# Generated by FakeRAM 2.0
VERSION 5.7 ;
BUSBITCHARS "[]" ;
PROPERTYDEFINITIONS
  MACRO width INTEGER ;
  MACRO depth INTEGER ;
  MACRO banks INTEGER ;
END PROPERTYDEFINITIONS
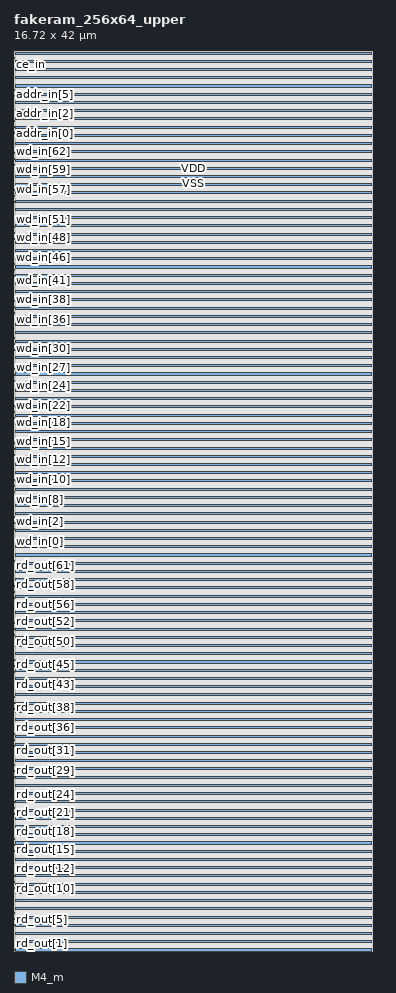
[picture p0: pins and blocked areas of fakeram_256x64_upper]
MACRO fakeram_256x64_upper
  PROPERTY width 64 ;
  PROPERTY depth 256 ;
  PROPERTY banks 2 ;
  FOREIGN fakeram_256x64_upper 0 0 ;
  SYMMETRY X Y R90 ;
  SIZE 16.720 BY 42.000 ;
  CLASS BLOCK ;
  PIN rd_out[0]
    DIRECTION OUTPUT ;
    USE SIGNAL ;
    SHAPE ABUTMENT ;
    PORT
      LAYER M4_m ;
      RECT 0.000 0.039 0.024 0.063 ;
    END
  END rd_out[0]
  PIN rd_out[1]
    DIRECTION OUTPUT ;
    USE SIGNAL ;
    SHAPE ABUTMENT ;
    PORT
      LAYER M4_m ;
      RECT 0.000 0.327 0.024 0.351 ;
    END
  END rd_out[1]
  PIN rd_out[2]
    DIRECTION OUTPUT ;
    USE SIGNAL ;
    SHAPE ABUTMENT ;
    PORT
      LAYER M4_m ;
      RECT 0.000 0.615 0.024 0.639 ;
    END
  END rd_out[2]
  PIN rd_out[3]
    DIRECTION OUTPUT ;
    USE SIGNAL ;
    SHAPE ABUTMENT ;
    PORT
      LAYER M4_m ;
      RECT 0.000 0.903 0.024 0.927 ;
    END
  END rd_out[3]
  PIN rd_out[4]
    DIRECTION OUTPUT ;
    USE SIGNAL ;
    SHAPE ABUTMENT ;
    PORT
      LAYER M4_m ;
      RECT 0.000 1.191 0.024 1.215 ;
    END
  END rd_out[4]
  PIN rd_out[5]
    DIRECTION OUTPUT ;
    USE SIGNAL ;
    SHAPE ABUTMENT ;
    PORT
      LAYER M4_m ;
      RECT 0.000 1.479 0.024 1.503 ;
    END
  END rd_out[5]
  PIN rd_out[6]
    DIRECTION OUTPUT ;
    USE SIGNAL ;
    SHAPE ABUTMENT ;
    PORT
      LAYER M4_m ;
      RECT 0.000 1.767 0.024 1.791 ;
    END
  END rd_out[6]
  PIN rd_out[7]
    DIRECTION OUTPUT ;
    USE SIGNAL ;
    SHAPE ABUTMENT ;
    PORT
      LAYER M4_m ;
      RECT 0.000 2.055 0.024 2.079 ;
    END
  END rd_out[7]
  PIN rd_out[8]
    DIRECTION OUTPUT ;
    USE SIGNAL ;
    SHAPE ABUTMENT ;
    PORT
      LAYER M4_m ;
      RECT 0.000 2.343 0.024 2.367 ;
    END
  END rd_out[8]
  PIN rd_out[9]
    DIRECTION OUTPUT ;
    USE SIGNAL ;
    SHAPE ABUTMENT ;
    PORT
      LAYER M4_m ;
      RECT 0.000 2.631 0.024 2.655 ;
    END
  END rd_out[9]
  PIN rd_out[10]
    DIRECTION OUTPUT ;
    USE SIGNAL ;
    SHAPE ABUTMENT ;
    PORT
      LAYER M4_m ;
      RECT 0.000 2.919 0.024 2.943 ;
    END
  END rd_out[10]
  PIN rd_out[11]
    DIRECTION OUTPUT ;
    USE SIGNAL ;
    SHAPE ABUTMENT ;
    PORT
      LAYER M4_m ;
      RECT 0.000 3.207 0.024 3.231 ;
    END
  END rd_out[11]
  PIN rd_out[12]
    DIRECTION OUTPUT ;
    USE SIGNAL ;
    SHAPE ABUTMENT ;
    PORT
      LAYER M4_m ;
      RECT 0.000 3.495 0.024 3.519 ;
    END
  END rd_out[12]
  PIN rd_out[13]
    DIRECTION OUTPUT ;
    USE SIGNAL ;
    SHAPE ABUTMENT ;
    PORT
      LAYER M4_m ;
      RECT 0.000 3.783 0.024 3.807 ;
    END
  END rd_out[13]
  PIN rd_out[14]
    DIRECTION OUTPUT ;
    USE SIGNAL ;
    SHAPE ABUTMENT ;
    PORT
      LAYER M4_m ;
      RECT 0.000 4.071 0.024 4.095 ;
    END
  END rd_out[14]
  PIN rd_out[15]
    DIRECTION OUTPUT ;
    USE SIGNAL ;
    SHAPE ABUTMENT ;
    PORT
      LAYER M4_m ;
      RECT 0.000 4.359 0.024 4.383 ;
    END
  END rd_out[15]
  PIN rd_out[16]
    DIRECTION OUTPUT ;
    USE SIGNAL ;
    SHAPE ABUTMENT ;
    PORT
      LAYER M4_m ;
      RECT 0.000 4.647 0.024 4.671 ;
    END
  END rd_out[16]
  PIN rd_out[17]
    DIRECTION OUTPUT ;
    USE SIGNAL ;
    SHAPE ABUTMENT ;
    PORT
      LAYER M4_m ;
      RECT 0.000 4.935 0.024 4.959 ;
    END
  END rd_out[17]
  PIN rd_out[18]
    DIRECTION OUTPUT ;
    USE SIGNAL ;
    SHAPE ABUTMENT ;
    PORT
      LAYER M4_m ;
      RECT 0.000 5.223 0.024 5.247 ;
    END
  END rd_out[18]
  PIN rd_out[19]
    DIRECTION OUTPUT ;
    USE SIGNAL ;
    SHAPE ABUTMENT ;
    PORT
      LAYER M4_m ;
      RECT 0.000 5.511 0.024 5.535 ;
    END
  END rd_out[19]
  PIN rd_out[20]
    DIRECTION OUTPUT ;
    USE SIGNAL ;
    SHAPE ABUTMENT ;
    PORT
      LAYER M4_m ;
      RECT 0.000 5.799 0.024 5.823 ;
    END
  END rd_out[20]
  PIN rd_out[21]
    DIRECTION OUTPUT ;
    USE SIGNAL ;
    SHAPE ABUTMENT ;
    PORT
      LAYER M4_m ;
      RECT 0.000 6.087 0.024 6.111 ;
    END
  END rd_out[21]
  PIN rd_out[22]
    DIRECTION OUTPUT ;
    USE SIGNAL ;
    SHAPE ABUTMENT ;
    PORT
      LAYER M4_m ;
      RECT 0.000 6.375 0.024 6.399 ;
    END
  END rd_out[22]
  PIN rd_out[23]
    DIRECTION OUTPUT ;
    USE SIGNAL ;
    SHAPE ABUTMENT ;
    PORT
      LAYER M4_m ;
      RECT 0.000 6.663 0.024 6.687 ;
    END
  END rd_out[23]
  PIN rd_out[24]
    DIRECTION OUTPUT ;
    USE SIGNAL ;
    SHAPE ABUTMENT ;
    PORT
      LAYER M4_m ;
      RECT 0.000 6.951 0.024 6.975 ;
    END
  END rd_out[24]
  PIN rd_out[25]
    DIRECTION OUTPUT ;
    USE SIGNAL ;
    SHAPE ABUTMENT ;
    PORT
      LAYER M4_m ;
      RECT 0.000 7.239 0.024 7.263 ;
    END
  END rd_out[25]
  PIN rd_out[26]
    DIRECTION OUTPUT ;
    USE SIGNAL ;
    SHAPE ABUTMENT ;
    PORT
      LAYER M4_m ;
      RECT 0.000 7.527 0.024 7.551 ;
    END
  END rd_out[26]
  PIN rd_out[27]
    DIRECTION OUTPUT ;
    USE SIGNAL ;
    SHAPE ABUTMENT ;
    PORT
      LAYER M4_m ;
      RECT 0.000 7.815 0.024 7.839 ;
    END
  END rd_out[27]
  PIN rd_out[28]
    DIRECTION OUTPUT ;
    USE SIGNAL ;
    SHAPE ABUTMENT ;
    PORT
      LAYER M4_m ;
      RECT 0.000 8.103 0.024 8.127 ;
    END
  END rd_out[28]
  PIN rd_out[29]
    DIRECTION OUTPUT ;
    USE SIGNAL ;
    SHAPE ABUTMENT ;
    PORT
      LAYER M4_m ;
      RECT 0.000 8.391 0.024 8.415 ;
    END
  END rd_out[29]
  PIN rd_out[30]
    DIRECTION OUTPUT ;
    USE SIGNAL ;
    SHAPE ABUTMENT ;
    PORT
      LAYER M4_m ;
      RECT 0.000 8.679 0.024 8.703 ;
    END
  END rd_out[30]
  PIN rd_out[31]
    DIRECTION OUTPUT ;
    USE SIGNAL ;
    SHAPE ABUTMENT ;
    PORT
      LAYER M4_m ;
      RECT 0.000 8.967 0.024 8.991 ;
    END
  END rd_out[31]
  PIN rd_out[32]
    DIRECTION OUTPUT ;
    USE SIGNAL ;
    SHAPE ABUTMENT ;
    PORT
      LAYER M4_m ;
      RECT 0.000 9.255 0.024 9.279 ;
    END
  END rd_out[32]
  PIN rd_out[33]
    DIRECTION OUTPUT ;
    USE SIGNAL ;
    SHAPE ABUTMENT ;
    PORT
      LAYER M4_m ;
      RECT 0.000 9.543 0.024 9.567 ;
    END
  END rd_out[33]
  PIN rd_out[34]
    DIRECTION OUTPUT ;
    USE SIGNAL ;
    SHAPE ABUTMENT ;
    PORT
      LAYER M4_m ;
      RECT 0.000 9.831 0.024 9.855 ;
    END
  END rd_out[34]
  PIN rd_out[35]
    DIRECTION OUTPUT ;
    USE SIGNAL ;
    SHAPE ABUTMENT ;
    PORT
      LAYER M4_m ;
      RECT 0.000 10.119 0.024 10.143 ;
    END
  END rd_out[35]
  PIN rd_out[36]
    DIRECTION OUTPUT ;
    USE SIGNAL ;
    SHAPE ABUTMENT ;
    PORT
      LAYER M4_m ;
      RECT 0.000 10.407 0.024 10.431 ;
    END
  END rd_out[36]
  PIN rd_out[37]
    DIRECTION OUTPUT ;
    USE SIGNAL ;
    SHAPE ABUTMENT ;
    PORT
      LAYER M4_m ;
      RECT 0.000 10.695 0.024 10.719 ;
    END
  END rd_out[37]
  PIN rd_out[38]
    DIRECTION OUTPUT ;
    USE SIGNAL ;
    SHAPE ABUTMENT ;
    PORT
      LAYER M4_m ;
      RECT 0.000 10.983 0.024 11.007 ;
    END
  END rd_out[38]
  PIN rd_out[39]
    DIRECTION OUTPUT ;
    USE SIGNAL ;
    SHAPE ABUTMENT ;
    PORT
      LAYER M4_m ;
      RECT 0.000 11.271 0.024 11.295 ;
    END
  END rd_out[39]
  PIN rd_out[40]
    DIRECTION OUTPUT ;
    USE SIGNAL ;
    SHAPE ABUTMENT ;
    PORT
      LAYER M4_m ;
      RECT 0.000 11.559 0.024 11.583 ;
    END
  END rd_out[40]
  PIN rd_out[41]
    DIRECTION OUTPUT ;
    USE SIGNAL ;
    SHAPE ABUTMENT ;
    PORT
      LAYER M4_m ;
      RECT 0.000 11.847 0.024 11.871 ;
    END
  END rd_out[41]
  PIN rd_out[42]
    DIRECTION OUTPUT ;
    USE SIGNAL ;
    SHAPE ABUTMENT ;
    PORT
      LAYER M4_m ;
      RECT 0.000 12.135 0.024 12.159 ;
    END
  END rd_out[42]
  PIN rd_out[43]
    DIRECTION OUTPUT ;
    USE SIGNAL ;
    SHAPE ABUTMENT ;
    PORT
      LAYER M4_m ;
      RECT 0.000 12.423 0.024 12.447 ;
    END
  END rd_out[43]
  PIN rd_out[44]
    DIRECTION OUTPUT ;
    USE SIGNAL ;
    SHAPE ABUTMENT ;
    PORT
      LAYER M4_m ;
      RECT 0.000 12.711 0.024 12.735 ;
    END
  END rd_out[44]
  PIN rd_out[45]
    DIRECTION OUTPUT ;
    USE SIGNAL ;
    SHAPE ABUTMENT ;
    PORT
      LAYER M4_m ;
      RECT 0.000 12.999 0.024 13.023 ;
    END
  END rd_out[45]
  PIN rd_out[46]
    DIRECTION OUTPUT ;
    USE SIGNAL ;
    SHAPE ABUTMENT ;
    PORT
      LAYER M4_m ;
      RECT 0.000 13.287 0.024 13.311 ;
    END
  END rd_out[46]
  PIN rd_out[47]
    DIRECTION OUTPUT ;
    USE SIGNAL ;
    SHAPE ABUTMENT ;
    PORT
      LAYER M4_m ;
      RECT 0.000 13.575 0.024 13.599 ;
    END
  END rd_out[47]
  PIN rd_out[48]
    DIRECTION OUTPUT ;
    USE SIGNAL ;
    SHAPE ABUTMENT ;
    PORT
      LAYER M4_m ;
      RECT 0.000 13.863 0.024 13.887 ;
    END
  END rd_out[48]
  PIN rd_out[49]
    DIRECTION OUTPUT ;
    USE SIGNAL ;
    SHAPE ABUTMENT ;
    PORT
      LAYER M4_m ;
      RECT 0.000 14.151 0.024 14.175 ;
    END
  END rd_out[49]
  PIN rd_out[50]
    DIRECTION OUTPUT ;
    USE SIGNAL ;
    SHAPE ABUTMENT ;
    PORT
      LAYER M4_m ;
      RECT 0.000 14.439 0.024 14.463 ;
    END
  END rd_out[50]
  PIN rd_out[51]
    DIRECTION OUTPUT ;
    USE SIGNAL ;
    SHAPE ABUTMENT ;
    PORT
      LAYER M4_m ;
      RECT 0.000 14.727 0.024 14.751 ;
    END
  END rd_out[51]
  PIN rd_out[52]
    DIRECTION OUTPUT ;
    USE SIGNAL ;
    SHAPE ABUTMENT ;
    PORT
      LAYER M4_m ;
      RECT 0.000 15.015 0.024 15.039 ;
    END
  END rd_out[52]
  PIN rd_out[53]
    DIRECTION OUTPUT ;
    USE SIGNAL ;
    SHAPE ABUTMENT ;
    PORT
      LAYER M4_m ;
      RECT 0.000 15.303 0.024 15.327 ;
    END
  END rd_out[53]
  PIN rd_out[54]
    DIRECTION OUTPUT ;
    USE SIGNAL ;
    SHAPE ABUTMENT ;
    PORT
      LAYER M4_m ;
      RECT 0.000 15.591 0.024 15.615 ;
    END
  END rd_out[54]
  PIN rd_out[55]
    DIRECTION OUTPUT ;
    USE SIGNAL ;
    SHAPE ABUTMENT ;
    PORT
      LAYER M4_m ;
      RECT 0.000 15.879 0.024 15.903 ;
    END
  END rd_out[55]
  PIN rd_out[56]
    DIRECTION OUTPUT ;
    USE SIGNAL ;
    SHAPE ABUTMENT ;
    PORT
      LAYER M4_m ;
      RECT 0.000 16.167 0.024 16.191 ;
    END
  END rd_out[56]
  PIN rd_out[57]
    DIRECTION OUTPUT ;
    USE SIGNAL ;
    SHAPE ABUTMENT ;
    PORT
      LAYER M4_m ;
      RECT 0.000 16.455 0.024 16.479 ;
    END
  END rd_out[57]
  PIN rd_out[58]
    DIRECTION OUTPUT ;
    USE SIGNAL ;
    SHAPE ABUTMENT ;
    PORT
      LAYER M4_m ;
      RECT 0.000 16.743 0.024 16.767 ;
    END
  END rd_out[58]
  PIN rd_out[59]
    DIRECTION OUTPUT ;
    USE SIGNAL ;
    SHAPE ABUTMENT ;
    PORT
      LAYER M4_m ;
      RECT 0.000 17.031 0.024 17.055 ;
    END
  END rd_out[59]
  PIN rd_out[60]
    DIRECTION OUTPUT ;
    USE SIGNAL ;
    SHAPE ABUTMENT ;
    PORT
      LAYER M4_m ;
      RECT 0.000 17.319 0.024 17.343 ;
    END
  END rd_out[60]
  PIN rd_out[61]
    DIRECTION OUTPUT ;
    USE SIGNAL ;
    SHAPE ABUTMENT ;
    PORT
      LAYER M4_m ;
      RECT 0.000 17.607 0.024 17.631 ;
    END
  END rd_out[61]
  PIN rd_out[62]
    DIRECTION OUTPUT ;
    USE SIGNAL ;
    SHAPE ABUTMENT ;
    PORT
      LAYER M4_m ;
      RECT 0.000 17.895 0.024 17.919 ;
    END
  END rd_out[62]
  PIN rd_out[63]
    DIRECTION OUTPUT ;
    USE SIGNAL ;
    SHAPE ABUTMENT ;
    PORT
      LAYER M4_m ;
      RECT 0.000 18.183 0.024 18.207 ;
    END
  END rd_out[63]
  PIN wd_in[0]
    DIRECTION INPUT ;
    USE SIGNAL ;
    SHAPE ABUTMENT ;
    PORT
      LAYER M4_m ;
      RECT 0.000 19.095 0.024 19.119 ;
    END
  END wd_in[0]
  PIN wd_in[1]
    DIRECTION INPUT ;
    USE SIGNAL ;
    SHAPE ABUTMENT ;
    PORT
      LAYER M4_m ;
      RECT 0.000 19.383 0.024 19.407 ;
    END
  END wd_in[1]
  PIN wd_in[2]
    DIRECTION INPUT ;
    USE SIGNAL ;
    SHAPE ABUTMENT ;
    PORT
      LAYER M4_m ;
      RECT 0.000 19.671 0.024 19.695 ;
    END
  END wd_in[2]
  PIN wd_in[3]
    DIRECTION INPUT ;
    USE SIGNAL ;
    SHAPE ABUTMENT ;
    PORT
      LAYER M4_m ;
      RECT 0.000 19.959 0.024 19.983 ;
    END
  END wd_in[3]
  PIN wd_in[4]
    DIRECTION INPUT ;
    USE SIGNAL ;
    SHAPE ABUTMENT ;
    PORT
      LAYER M4_m ;
      RECT 0.000 20.247 0.024 20.271 ;
    END
  END wd_in[4]
  PIN wd_in[5]
    DIRECTION INPUT ;
    USE SIGNAL ;
    SHAPE ABUTMENT ;
    PORT
      LAYER M4_m ;
      RECT 0.000 20.535 0.024 20.559 ;
    END
  END wd_in[5]
  PIN wd_in[6]
    DIRECTION INPUT ;
    USE SIGNAL ;
    SHAPE ABUTMENT ;
    PORT
      LAYER M4_m ;
      RECT 0.000 20.823 0.024 20.847 ;
    END
  END wd_in[6]
  PIN wd_in[7]
    DIRECTION INPUT ;
    USE SIGNAL ;
    SHAPE ABUTMENT ;
    PORT
      LAYER M4_m ;
      RECT 0.000 21.111 0.024 21.135 ;
    END
  END wd_in[7]
  PIN wd_in[8]
    DIRECTION INPUT ;
    USE SIGNAL ;
    SHAPE ABUTMENT ;
    PORT
      LAYER M4_m ;
      RECT 0.000 21.399 0.024 21.423 ;
    END
  END wd_in[8]
  PIN wd_in[9]
    DIRECTION INPUT ;
    USE SIGNAL ;
    SHAPE ABUTMENT ;
    PORT
      LAYER M4_m ;
      RECT 0.000 21.687 0.024 21.711 ;
    END
  END wd_in[9]
  PIN wd_in[10]
    DIRECTION INPUT ;
    USE SIGNAL ;
    SHAPE ABUTMENT ;
    PORT
      LAYER M4_m ;
      RECT 0.000 21.975 0.024 21.999 ;
    END
  END wd_in[10]
  PIN wd_in[11]
    DIRECTION INPUT ;
    USE SIGNAL ;
    SHAPE ABUTMENT ;
    PORT
      LAYER M4_m ;
      RECT 0.000 22.263 0.024 22.287 ;
    END
  END wd_in[11]
  PIN wd_in[12]
    DIRECTION INPUT ;
    USE SIGNAL ;
    SHAPE ABUTMENT ;
    PORT
      LAYER M4_m ;
      RECT 0.000 22.551 0.024 22.575 ;
    END
  END wd_in[12]
  PIN wd_in[13]
    DIRECTION INPUT ;
    USE SIGNAL ;
    SHAPE ABUTMENT ;
    PORT
      LAYER M4_m ;
      RECT 0.000 22.839 0.024 22.863 ;
    END
  END wd_in[13]
  PIN wd_in[14]
    DIRECTION INPUT ;
    USE SIGNAL ;
    SHAPE ABUTMENT ;
    PORT
      LAYER M4_m ;
      RECT 0.000 23.127 0.024 23.151 ;
    END
  END wd_in[14]
  PIN wd_in[15]
    DIRECTION INPUT ;
    USE SIGNAL ;
    SHAPE ABUTMENT ;
    PORT
      LAYER M4_m ;
      RECT 0.000 23.415 0.024 23.439 ;
    END
  END wd_in[15]
  PIN wd_in[16]
    DIRECTION INPUT ;
    USE SIGNAL ;
    SHAPE ABUTMENT ;
    PORT
      LAYER M4_m ;
      RECT 0.000 23.703 0.024 23.727 ;
    END
  END wd_in[16]
  PIN wd_in[17]
    DIRECTION INPUT ;
    USE SIGNAL ;
    SHAPE ABUTMENT ;
    PORT
      LAYER M4_m ;
      RECT 0.000 23.991 0.024 24.015 ;
    END
  END wd_in[17]
  PIN wd_in[18]
    DIRECTION INPUT ;
    USE SIGNAL ;
    SHAPE ABUTMENT ;
    PORT
      LAYER M4_m ;
      RECT 0.000 24.279 0.024 24.303 ;
    END
  END wd_in[18]
  PIN wd_in[19]
    DIRECTION INPUT ;
    USE SIGNAL ;
    SHAPE ABUTMENT ;
    PORT
      LAYER M4_m ;
      RECT 0.000 24.567 0.024 24.591 ;
    END
  END wd_in[19]
  PIN wd_in[20]
    DIRECTION INPUT ;
    USE SIGNAL ;
    SHAPE ABUTMENT ;
    PORT
      LAYER M4_m ;
      RECT 0.000 24.855 0.024 24.879 ;
    END
  END wd_in[20]
  PIN wd_in[21]
    DIRECTION INPUT ;
    USE SIGNAL ;
    SHAPE ABUTMENT ;
    PORT
      LAYER M4_m ;
      RECT 0.000 25.143 0.024 25.167 ;
    END
  END wd_in[21]
  PIN wd_in[22]
    DIRECTION INPUT ;
    USE SIGNAL ;
    SHAPE ABUTMENT ;
    PORT
      LAYER M4_m ;
      RECT 0.000 25.431 0.024 25.455 ;
    END
  END wd_in[22]
  PIN wd_in[23]
    DIRECTION INPUT ;
    USE SIGNAL ;
    SHAPE ABUTMENT ;
    PORT
      LAYER M4_m ;
      RECT 0.000 25.719 0.024 25.743 ;
    END
  END wd_in[23]
  PIN wd_in[24]
    DIRECTION INPUT ;
    USE SIGNAL ;
    SHAPE ABUTMENT ;
    PORT
      LAYER M4_m ;
      RECT 0.000 26.007 0.024 26.031 ;
    END
  END wd_in[24]
  PIN wd_in[25]
    DIRECTION INPUT ;
    USE SIGNAL ;
    SHAPE ABUTMENT ;
    PORT
      LAYER M4_m ;
      RECT 0.000 26.295 0.024 26.319 ;
    END
  END wd_in[25]
  PIN wd_in[26]
    DIRECTION INPUT ;
    USE SIGNAL ;
    SHAPE ABUTMENT ;
    PORT
      LAYER M4_m ;
      RECT 0.000 26.583 0.024 26.607 ;
    END
  END wd_in[26]
  PIN wd_in[27]
    DIRECTION INPUT ;
    USE SIGNAL ;
    SHAPE ABUTMENT ;
    PORT
      LAYER M4_m ;
      RECT 0.000 26.871 0.024 26.895 ;
    END
  END wd_in[27]
  PIN wd_in[28]
    DIRECTION INPUT ;
    USE SIGNAL ;
    SHAPE ABUTMENT ;
    PORT
      LAYER M4_m ;
      RECT 0.000 27.159 0.024 27.183 ;
    END
  END wd_in[28]
  PIN wd_in[29]
    DIRECTION INPUT ;
    USE SIGNAL ;
    SHAPE ABUTMENT ;
    PORT
      LAYER M4_m ;
      RECT 0.000 27.447 0.024 27.471 ;
    END
  END wd_in[29]
  PIN wd_in[30]
    DIRECTION INPUT ;
    USE SIGNAL ;
    SHAPE ABUTMENT ;
    PORT
      LAYER M4_m ;
      RECT 0.000 27.735 0.024 27.759 ;
    END
  END wd_in[30]
  PIN wd_in[31]
    DIRECTION INPUT ;
    USE SIGNAL ;
    SHAPE ABUTMENT ;
    PORT
      LAYER M4_m ;
      RECT 0.000 28.023 0.024 28.047 ;
    END
  END wd_in[31]
  PIN wd_in[32]
    DIRECTION INPUT ;
    USE SIGNAL ;
    SHAPE ABUTMENT ;
    PORT
      LAYER M4_m ;
      RECT 0.000 28.311 0.024 28.335 ;
    END
  END wd_in[32]
  PIN wd_in[33]
    DIRECTION INPUT ;
    USE SIGNAL ;
    SHAPE ABUTMENT ;
    PORT
      LAYER M4_m ;
      RECT 0.000 28.599 0.024 28.623 ;
    END
  END wd_in[33]
  PIN wd_in[34]
    DIRECTION INPUT ;
    USE SIGNAL ;
    SHAPE ABUTMENT ;
    PORT
      LAYER M4_m ;
      RECT 0.000 28.887 0.024 28.911 ;
    END
  END wd_in[34]
  PIN wd_in[35]
    DIRECTION INPUT ;
    USE SIGNAL ;
    SHAPE ABUTMENT ;
    PORT
      LAYER M4_m ;
      RECT 0.000 29.175 0.024 29.199 ;
    END
  END wd_in[35]
  PIN wd_in[36]
    DIRECTION INPUT ;
    USE SIGNAL ;
    SHAPE ABUTMENT ;
    PORT
      LAYER M4_m ;
      RECT 0.000 29.463 0.024 29.487 ;
    END
  END wd_in[36]
  PIN wd_in[37]
    DIRECTION INPUT ;
    USE SIGNAL ;
    SHAPE ABUTMENT ;
    PORT
      LAYER M4_m ;
      RECT 0.000 29.751 0.024 29.775 ;
    END
  END wd_in[37]
  PIN wd_in[38]
    DIRECTION INPUT ;
    USE SIGNAL ;
    SHAPE ABUTMENT ;
    PORT
      LAYER M4_m ;
      RECT 0.000 30.039 0.024 30.063 ;
    END
  END wd_in[38]
  PIN wd_in[39]
    DIRECTION INPUT ;
    USE SIGNAL ;
    SHAPE ABUTMENT ;
    PORT
      LAYER M4_m ;
      RECT 0.000 30.327 0.024 30.351 ;
    END
  END wd_in[39]
  PIN wd_in[40]
    DIRECTION INPUT ;
    USE SIGNAL ;
    SHAPE ABUTMENT ;
    PORT
      LAYER M4_m ;
      RECT 0.000 30.615 0.024 30.639 ;
    END
  END wd_in[40]
  PIN wd_in[41]
    DIRECTION INPUT ;
    USE SIGNAL ;
    SHAPE ABUTMENT ;
    PORT
      LAYER M4_m ;
      RECT 0.000 30.903 0.024 30.927 ;
    END
  END wd_in[41]
  PIN wd_in[42]
    DIRECTION INPUT ;
    USE SIGNAL ;
    SHAPE ABUTMENT ;
    PORT
      LAYER M4_m ;
      RECT 0.000 31.191 0.024 31.215 ;
    END
  END wd_in[42]
  PIN wd_in[43]
    DIRECTION INPUT ;
    USE SIGNAL ;
    SHAPE ABUTMENT ;
    PORT
      LAYER M4_m ;
      RECT 0.000 31.479 0.024 31.503 ;
    END
  END wd_in[43]
  PIN wd_in[44]
    DIRECTION INPUT ;
    USE SIGNAL ;
    SHAPE ABUTMENT ;
    PORT
      LAYER M4_m ;
      RECT 0.000 31.767 0.024 31.791 ;
    END
  END wd_in[44]
  PIN wd_in[45]
    DIRECTION INPUT ;
    USE SIGNAL ;
    SHAPE ABUTMENT ;
    PORT
      LAYER M4_m ;
      RECT 0.000 32.055 0.024 32.079 ;
    END
  END wd_in[45]
  PIN wd_in[46]
    DIRECTION INPUT ;
    USE SIGNAL ;
    SHAPE ABUTMENT ;
    PORT
      LAYER M4_m ;
      RECT 0.000 32.343 0.024 32.367 ;
    END
  END wd_in[46]
  PIN wd_in[47]
    DIRECTION INPUT ;
    USE SIGNAL ;
    SHAPE ABUTMENT ;
    PORT
      LAYER M4_m ;
      RECT 0.000 32.631 0.024 32.655 ;
    END
  END wd_in[47]
  PIN wd_in[48]
    DIRECTION INPUT ;
    USE SIGNAL ;
    SHAPE ABUTMENT ;
    PORT
      LAYER M4_m ;
      RECT 0.000 32.919 0.024 32.943 ;
    END
  END wd_in[48]
  PIN wd_in[49]
    DIRECTION INPUT ;
    USE SIGNAL ;
    SHAPE ABUTMENT ;
    PORT
      LAYER M4_m ;
      RECT 0.000 33.207 0.024 33.231 ;
    END
  END wd_in[49]
  PIN wd_in[50]
    DIRECTION INPUT ;
    USE SIGNAL ;
    SHAPE ABUTMENT ;
    PORT
      LAYER M4_m ;
      RECT 0.000 33.495 0.024 33.519 ;
    END
  END wd_in[50]
  PIN wd_in[51]
    DIRECTION INPUT ;
    USE SIGNAL ;
    SHAPE ABUTMENT ;
    PORT
      LAYER M4_m ;
      RECT 0.000 33.783 0.024 33.807 ;
    END
  END wd_in[51]
  PIN wd_in[52]
    DIRECTION INPUT ;
    USE SIGNAL ;
    SHAPE ABUTMENT ;
    PORT
      LAYER M4_m ;
      RECT 0.000 34.071 0.024 34.095 ;
    END
  END wd_in[52]
  PIN wd_in[53]
    DIRECTION INPUT ;
    USE SIGNAL ;
    SHAPE ABUTMENT ;
    PORT
      LAYER M4_m ;
      RECT 0.000 34.359 0.024 34.383 ;
    END
  END wd_in[53]
  PIN wd_in[54]
    DIRECTION INPUT ;
    USE SIGNAL ;
    SHAPE ABUTMENT ;
    PORT
      LAYER M4_m ;
      RECT 0.000 34.647 0.024 34.671 ;
    END
  END wd_in[54]
  PIN wd_in[55]
    DIRECTION INPUT ;
    USE SIGNAL ;
    SHAPE ABUTMENT ;
    PORT
      LAYER M4_m ;
      RECT 0.000 34.935 0.024 34.959 ;
    END
  END wd_in[55]
  PIN wd_in[56]
    DIRECTION INPUT ;
    USE SIGNAL ;
    SHAPE ABUTMENT ;
    PORT
      LAYER M4_m ;
      RECT 0.000 35.223 0.024 35.247 ;
    END
  END wd_in[56]
  PIN wd_in[57]
    DIRECTION INPUT ;
    USE SIGNAL ;
    SHAPE ABUTMENT ;
    PORT
      LAYER M4_m ;
      RECT 0.000 35.511 0.024 35.535 ;
    END
  END wd_in[57]
  PIN wd_in[58]
    DIRECTION INPUT ;
    USE SIGNAL ;
    SHAPE ABUTMENT ;
    PORT
      LAYER M4_m ;
      RECT 0.000 35.799 0.024 35.823 ;
    END
  END wd_in[58]
  PIN wd_in[59]
    DIRECTION INPUT ;
    USE SIGNAL ;
    SHAPE ABUTMENT ;
    PORT
      LAYER M4_m ;
      RECT 0.000 36.087 0.024 36.111 ;
    END
  END wd_in[59]
  PIN wd_in[60]
    DIRECTION INPUT ;
    USE SIGNAL ;
    SHAPE ABUTMENT ;
    PORT
      LAYER M4_m ;
      RECT 0.000 36.375 0.024 36.399 ;
    END
  END wd_in[60]
  PIN wd_in[61]
    DIRECTION INPUT ;
    USE SIGNAL ;
    SHAPE ABUTMENT ;
    PORT
      LAYER M4_m ;
      RECT 0.000 36.663 0.024 36.687 ;
    END
  END wd_in[61]
  PIN wd_in[62]
    DIRECTION INPUT ;
    USE SIGNAL ;
    SHAPE ABUTMENT ;
    PORT
      LAYER M4_m ;
      RECT 0.000 36.951 0.024 36.975 ;
    END
  END wd_in[62]
  PIN wd_in[63]
    DIRECTION INPUT ;
    USE SIGNAL ;
    SHAPE ABUTMENT ;
    PORT
      LAYER M4_m ;
      RECT 0.000 37.239 0.024 37.263 ;
    END
  END wd_in[63]
  PIN addr_in[0]
    DIRECTION INPUT ;
    USE SIGNAL ;
    SHAPE ABUTMENT ;
    PORT
      LAYER M4_m ;
      RECT 0.000 38.151 0.024 38.175 ;
    END
  END addr_in[0]
  PIN addr_in[1]
    DIRECTION INPUT ;
    USE SIGNAL ;
    SHAPE ABUTMENT ;
    PORT
      LAYER M4_m ;
      RECT 0.000 38.439 0.024 38.463 ;
    END
  END addr_in[1]
  PIN addr_in[2]
    DIRECTION INPUT ;
    USE SIGNAL ;
    SHAPE ABUTMENT ;
    PORT
      LAYER M4_m ;
      RECT 0.000 38.727 0.024 38.751 ;
    END
  END addr_in[2]
  PIN addr_in[3]
    DIRECTION INPUT ;
    USE SIGNAL ;
    SHAPE ABUTMENT ;
    PORT
      LAYER M4_m ;
      RECT 0.000 39.015 0.024 39.039 ;
    END
  END addr_in[3]
  PIN addr_in[4]
    DIRECTION INPUT ;
    USE SIGNAL ;
    SHAPE ABUTMENT ;
    PORT
      LAYER M4_m ;
      RECT 0.000 39.303 0.024 39.327 ;
    END
  END addr_in[4]
  PIN addr_in[5]
    DIRECTION INPUT ;
    USE SIGNAL ;
    SHAPE ABUTMENT ;
    PORT
      LAYER M4_m ;
      RECT 0.000 39.591 0.024 39.615 ;
    END
  END addr_in[5]
  PIN addr_in[6]
    DIRECTION INPUT ;
    USE SIGNAL ;
    SHAPE ABUTMENT ;
    PORT
      LAYER M4_m ;
      RECT 0.000 39.879 0.024 39.903 ;
    END
  END addr_in[6]
  PIN addr_in[7]
    DIRECTION INPUT ;
    USE SIGNAL ;
    SHAPE ABUTMENT ;
    PORT
      LAYER M4_m ;
      RECT 0.000 40.167 0.024 40.191 ;
    END
  END addr_in[7]
  PIN we_in
    DIRECTION INPUT ;
    USE SIGNAL ;
    SHAPE ABUTMENT ;
    PORT
      LAYER M4_m ;
      RECT 0.000 41.079 0.024 41.103 ;
    END
  END we_in
  PIN ce_in
    DIRECTION INPUT ;
    USE SIGNAL ;
    SHAPE ABUTMENT ;
    PORT
      LAYER M4_m ;
      RECT 0.000 41.367 0.024 41.391 ;
    END
  END ce_in
  PIN clk
    DIRECTION INPUT ;
    USE SIGNAL ;
    SHAPE ABUTMENT ;
    PORT
      LAYER M4_m ;
      RECT 0.000 41.655 0.024 41.679 ;
    END
  END clk
  PIN VSS
    DIRECTION INOUT ;
    USE GROUND ;
    PORT
      LAYER M4_m ;
      RECT 0.048 0.000 16.672 0.096 ;
      RECT 0.048 0.768 16.672 0.864 ;
      RECT 0.048 1.536 16.672 1.632 ;
      RECT 0.048 2.304 16.672 2.400 ;
      RECT 0.048 3.072 16.672 3.168 ;
      RECT 0.048 3.840 16.672 3.936 ;
      RECT 0.048 4.608 16.672 4.704 ;
      RECT 0.048 5.376 16.672 5.472 ;
      RECT 0.048 6.144 16.672 6.240 ;
      RECT 0.048 6.912 16.672 7.008 ;
      RECT 0.048 7.680 16.672 7.776 ;
      RECT 0.048 8.448 16.672 8.544 ;
      RECT 0.048 9.216 16.672 9.312 ;
      RECT 0.048 9.984 16.672 10.080 ;
      RECT 0.048 10.752 16.672 10.848 ;
      RECT 0.048 11.520 16.672 11.616 ;
      RECT 0.048 12.288 16.672 12.384 ;
      RECT 0.048 13.056 16.672 13.152 ;
      RECT 0.048 13.824 16.672 13.920 ;
      RECT 0.048 14.592 16.672 14.688 ;
      RECT 0.048 15.360 16.672 15.456 ;
      RECT 0.048 16.128 16.672 16.224 ;
      RECT 0.048 16.896 16.672 16.992 ;
      RECT 0.048 17.664 16.672 17.760 ;
      RECT 0.048 18.432 16.672 18.528 ;
      RECT 0.048 19.200 16.672 19.296 ;
      RECT 0.048 19.968 16.672 20.064 ;
      RECT 0.048 20.736 16.672 20.832 ;
      RECT 0.048 21.504 16.672 21.600 ;
      RECT 0.048 22.272 16.672 22.368 ;
      RECT 0.048 23.040 16.672 23.136 ;
      RECT 0.048 23.808 16.672 23.904 ;
      RECT 0.048 24.576 16.672 24.672 ;
      RECT 0.048 25.344 16.672 25.440 ;
      RECT 0.048 26.112 16.672 26.208 ;
      RECT 0.048 26.880 16.672 26.976 ;
      RECT 0.048 27.648 16.672 27.744 ;
      RECT 0.048 28.416 16.672 28.512 ;
      RECT 0.048 29.184 16.672 29.280 ;
      RECT 0.048 29.952 16.672 30.048 ;
      RECT 0.048 30.720 16.672 30.816 ;
      RECT 0.048 31.488 16.672 31.584 ;
      RECT 0.048 32.256 16.672 32.352 ;
      RECT 0.048 33.024 16.672 33.120 ;
      RECT 0.048 33.792 16.672 33.888 ;
      RECT 0.048 34.560 16.672 34.656 ;
      RECT 0.048 35.328 16.672 35.424 ;
      RECT 0.048 36.096 16.672 36.192 ;
      RECT 0.048 36.864 16.672 36.960 ;
      RECT 0.048 37.632 16.672 37.728 ;
      RECT 0.048 38.400 16.672 38.496 ;
      RECT 0.048 39.168 16.672 39.264 ;
      RECT 0.048 39.936 16.672 40.032 ;
      RECT 0.048 40.704 16.672 40.800 ;
      RECT 0.048 41.472 16.672 41.568 ;
    END
  END VSS
  PIN VDD
    DIRECTION INOUT ;
    USE POWER ;
    PORT
      LAYER M4_m ;
      RECT 0.048 0.384 16.672 0.480 ;
      RECT 0.048 1.152 16.672 1.248 ;
      RECT 0.048 1.920 16.672 2.016 ;
      RECT 0.048 2.688 16.672 2.784 ;
      RECT 0.048 3.456 16.672 3.552 ;
      RECT 0.048 4.224 16.672 4.320 ;
      RECT 0.048 4.992 16.672 5.088 ;
      RECT 0.048 5.760 16.672 5.856 ;
      RECT 0.048 6.528 16.672 6.624 ;
      RECT 0.048 7.296 16.672 7.392 ;
      RECT 0.048 8.064 16.672 8.160 ;
      RECT 0.048 8.832 16.672 8.928 ;
      RECT 0.048 9.600 16.672 9.696 ;
      RECT 0.048 10.368 16.672 10.464 ;
      RECT 0.048 11.136 16.672 11.232 ;
      RECT 0.048 11.904 16.672 12.000 ;
      RECT 0.048 12.672 16.672 12.768 ;
      RECT 0.048 13.440 16.672 13.536 ;
      RECT 0.048 14.208 16.672 14.304 ;
      RECT 0.048 14.976 16.672 15.072 ;
      RECT 0.048 15.744 16.672 15.840 ;
      RECT 0.048 16.512 16.672 16.608 ;
      RECT 0.048 17.280 16.672 17.376 ;
      RECT 0.048 18.048 16.672 18.144 ;
      RECT 0.048 18.816 16.672 18.912 ;
      RECT 0.048 19.584 16.672 19.680 ;
      RECT 0.048 20.352 16.672 20.448 ;
      RECT 0.048 21.120 16.672 21.216 ;
      RECT 0.048 21.888 16.672 21.984 ;
      RECT 0.048 22.656 16.672 22.752 ;
      RECT 0.048 23.424 16.672 23.520 ;
      RECT 0.048 24.192 16.672 24.288 ;
      RECT 0.048 24.960 16.672 25.056 ;
      RECT 0.048 25.728 16.672 25.824 ;
      RECT 0.048 26.496 16.672 26.592 ;
      RECT 0.048 27.264 16.672 27.360 ;
      RECT 0.048 28.032 16.672 28.128 ;
      RECT 0.048 28.800 16.672 28.896 ;
      RECT 0.048 29.568 16.672 29.664 ;
      RECT 0.048 30.336 16.672 30.432 ;
      RECT 0.048 31.104 16.672 31.200 ;
      RECT 0.048 31.872 16.672 31.968 ;
      RECT 0.048 32.640 16.672 32.736 ;
      RECT 0.048 33.408 16.672 33.504 ;
      RECT 0.048 34.176 16.672 34.272 ;
      RECT 0.048 34.944 16.672 35.040 ;
      RECT 0.048 35.712 16.672 35.808 ;
      RECT 0.048 36.480 16.672 36.576 ;
      RECT 0.048 37.248 16.672 37.344 ;
      RECT 0.048 38.016 16.672 38.112 ;
      RECT 0.048 38.784 16.672 38.880 ;
      RECT 0.048 39.552 16.672 39.648 ;
      RECT 0.048 40.320 16.672 40.416 ;
      RECT 0.048 41.088 16.672 41.184 ;
      RECT 0.048 41.856 16.672 41.952 ;
    END
  END VDD
  OBS
    LAYER M1_m ;
    RECT 0 0 16.720 42.000 ;
    LAYER M2_m ;
    RECT 0 0 16.720 42.000 ;
    LAYER M3_m ;
    RECT 0.059 0.000 16.720 42.000 ;
    LAYER M4_m ;
    RECT 0.059 0.000 16.720 42.000 ;
  END
END fakeram_256x64_upper

END LIBRARY
